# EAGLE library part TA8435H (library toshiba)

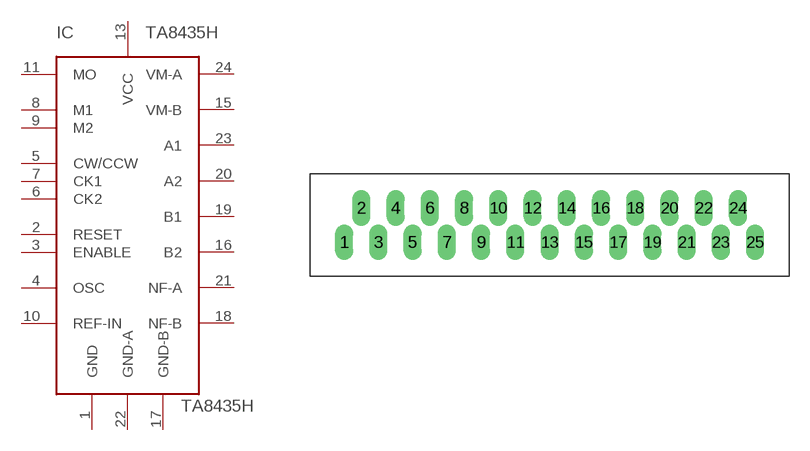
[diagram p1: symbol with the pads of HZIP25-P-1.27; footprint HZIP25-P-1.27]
Designator prefix IC

## TA8435H  [HZIP25-P-1.27]
1  GND  sup
2  RESET  in
3  ENABLE  in
4  OSC  pas
5  CW/CCW  in
6  CK2  in
7  CK1  in
8  M1  in
9  M2  in
10  REF-IN  in
11  MO  out
13  VCC  pwr
15  VM-B  pwr
16  B2
17  GND-B  sup
18  NF-B  pas
19  B1
20  A2
21  NF-A  pas
22  GND-A  sup
23  A1
24  VM-A  pwr

## Footprint HZIP25-P-1.27 (pad centres in mm)
drill 0.813 long: 1 -17.78,-5.08; 2 -16.51,-2.54; 3 -15.24,-5.08; 4 -13.97,-2.54; 5 -12.7,-5.08; 6 -11.43,-2.54; 7 -10.16,-5.08; 8 -8.89,-2.54; 9 -7.62,-5.08; 10 -6.35,-2.54; 11 -5.08,-5.08; 12 -3.81,-2.54; 13 -2.54,-5.08; 14 -1.27,-2.54; 15 0,-5.08; 16 1.27,-2.54; 17 2.54,-5.08; 18 3.81,-2.54; 19 5.08,-5.08; 20 6.35,-2.54; 21 7.62,-5.08; 22 8.89,-2.54; 23 10.16,-5.08; 24 11.43,-2.54; 25 12.7,-5.08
